VERSION 5.7 ;
  NOWIREEXTENSIONATPIN ON ;
  DIVIDERCHAR "/" ;
  BUSBITCHARS "[]" ;
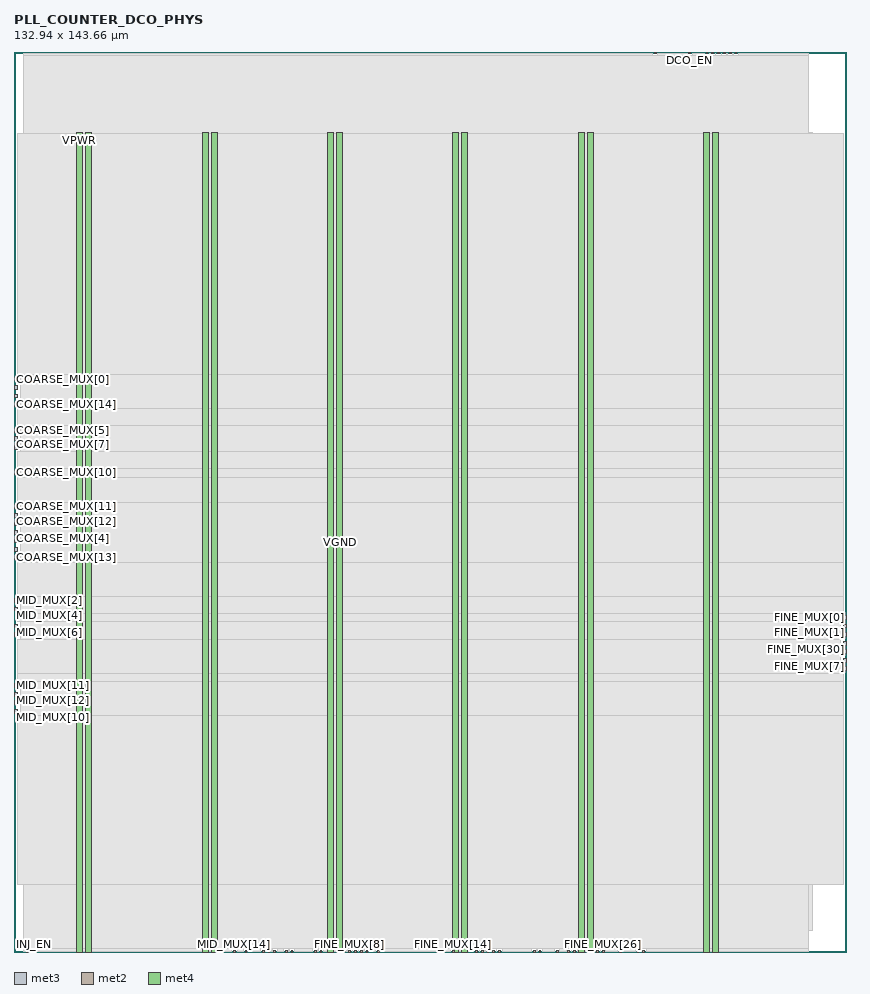
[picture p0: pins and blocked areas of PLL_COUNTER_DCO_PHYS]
MACRO PLL_COUNTER_DCO_PHYS
  CLASS BLOCK ;
  FOREIGN PLL_COUNTER_DCO_PHYS ;
  ORIGIN 0.000 0.000 ;
  SIZE 132.940 BY 143.660 ;
  PIN COARSE_MUX[0]
    DIRECTION INPUT ;
    USE SIGNAL ;
    ANTENNAGATEAREA 0.213000 ;
    PORT
      LAYER met3 ;
        RECT 0.000 91.160 0.600 91.760 ;
    END
  END COARSE_MUX[0]
  PIN COARSE_MUX[10]
    DIRECTION INPUT ;
    USE SIGNAL ;
    ANTENNAGATEAREA 0.213000 ;
    PORT
      LAYER met3 ;
        RECT 0.000 76.200 0.600 76.800 ;
    END
  END COARSE_MUX[10]
  PIN COARSE_MUX[11]
    DIRECTION INPUT ;
    USE SIGNAL ;
    ANTENNAGATEAREA 0.213000 ;
    PORT
      LAYER met3 ;
        RECT 0.000 70.760 0.600 71.360 ;
    END
  END COARSE_MUX[11]
  PIN COARSE_MUX[12]
    DIRECTION INPUT ;
    USE SIGNAL ;
    ANTENNAGATEAREA 0.213000 ;
    PORT
      LAYER met3 ;
        RECT 0.000 69.400 0.600 70.000 ;
    END
  END COARSE_MUX[12]
  PIN COARSE_MUX[13]
    DIRECTION INPUT ;
    USE SIGNAL ;
    ANTENNAGATEAREA 0.213000 ;
    PORT
      LAYER met3 ;
        RECT 0.000 62.600 0.600 63.200 ;
    END
  END COARSE_MUX[13]
  PIN COARSE_MUX[14]
    DIRECTION INPUT ;
    USE SIGNAL ;
    ANTENNAGATEAREA 0.213000 ;
    PORT
      LAYER met3 ;
        RECT 0.000 87.080 0.600 87.680 ;
    END
  END COARSE_MUX[14]
  PIN COARSE_MUX[1]
    DIRECTION INPUT ;
    USE SIGNAL ;
    ANTENNAGATEAREA 0.213000 ;
    PORT
      LAYER met3 ;
        RECT 0.000 89.800 0.600 90.400 ;
    END
  END COARSE_MUX[1]
  PIN COARSE_MUX[2]
    DIRECTION INPUT ;
    USE SIGNAL ;
    ANTENNAGATEAREA 0.213000 ;
    PORT
      LAYER met3 ;
        RECT 0.000 68.040 0.600 68.640 ;
    END
  END COARSE_MUX[2]
  PIN COARSE_MUX[3]
    DIRECTION INPUT ;
    USE SIGNAL ;
    ANTENNAGATEAREA 0.213000 ;
    PORT
      LAYER met3 ;
        RECT 0.000 88.440 0.600 89.040 ;
    END
  END COARSE_MUX[3]
  PIN COARSE_MUX[4]
    DIRECTION INPUT ;
    USE SIGNAL ;
    ANTENNAGATEAREA 0.213000 ;
    PORT
      LAYER met3 ;
        RECT 0.000 66.680 0.600 67.280 ;
    END
  END COARSE_MUX[4]
  PIN COARSE_MUX[5]
    DIRECTION INPUT ;
    USE SIGNAL ;
    ANTENNAGATEAREA 0.213000 ;
    PORT
      LAYER met3 ;
        RECT 0.000 83.000 0.600 83.600 ;
    END
  END COARSE_MUX[5]
  PIN COARSE_MUX[6]
    DIRECTION INPUT ;
    USE SIGNAL ;
    ANTENNAGATEAREA 0.213000 ;
    PORT
      LAYER met3 ;
        RECT 0.000 63.960 0.600 64.560 ;
    END
  END COARSE_MUX[6]
  PIN COARSE_MUX[7]
    DIRECTION INPUT ;
    USE SIGNAL ;
    ANTENNAGATEAREA 0.213000 ;
    PORT
      LAYER met3 ;
        RECT 0.000 81.640 0.600 82.240 ;
    END
  END COARSE_MUX[7]
  PIN COARSE_MUX[8]
    DIRECTION INPUT ;
    USE SIGNAL ;
    ANTENNAGATEAREA 0.213000 ;
    PORT
      LAYER met3 ;
        RECT 0.000 65.320 0.600 65.920 ;
    END
  END COARSE_MUX[8]
  PIN COARSE_MUX[9]
    DIRECTION INPUT ;
    USE SIGNAL ;
    ANTENNAGATEAREA 0.213000 ;
    PORT
      LAYER met3 ;
        RECT 0.000 80.280 0.600 80.880 ;
    END
  END COARSE_MUX[9]
  PIN DCO_EN
    DIRECTION INPUT ;
    USE SIGNAL ;
    ANTENNAGATEAREA 0.213000 ;
    PORT
      LAYER met2 ;
        RECT 107.730 143.380 108.010 143.660 ;
    END
  END DCO_EN
  PIN FINE_MUX[0]
    DIRECTION INPUT ;
    USE SIGNAL ;
    ANTENNAGATEAREA 0.213000 ;
    PORT
      LAYER met3 ;
        RECT 132.340 53.080 132.940 53.680 ;
    END
  END FINE_MUX[0]
  PIN FINE_MUX[10]
    DIRECTION INPUT ;
    USE SIGNAL ;
    ANTENNAGATEAREA 0.213000 ;
    PORT
      LAYER met2 ;
        RECT 58.050 0.000 58.330 0.280 ;
    END
  END FINE_MUX[10]
  PIN FINE_MUX[11]
    DIRECTION INPUT ;
    USE SIGNAL ;
    ANTENNAGATEAREA 0.213000 ;
    PORT
      LAYER met2 ;
        RECT 100.370 0.000 100.650 0.280 ;
    END
  END FINE_MUX[11]
  PIN FINE_MUX[12]
    DIRECTION INPUT ;
    USE SIGNAL ;
    ANTENNAGATEAREA 0.213000 ;
    PORT
      LAYER met2 ;
        RECT 55.290 0.000 55.570 0.280 ;
    END
  END FINE_MUX[12]
  PIN FINE_MUX[13]
    DIRECTION INPUT ;
    USE SIGNAL ;
    ANTENNAGATEAREA 0.213000 ;
    PORT
      LAYER met2 ;
        RECT 99.450 0.000 99.730 0.280 ;
    END
  END FINE_MUX[13]
  PIN FINE_MUX[14]
    DIRECTION INPUT ;
    USE SIGNAL ;
    ANTENNAGATEAREA 0.213000 ;
    PORT
      LAYER met2 ;
        RECT 70.010 0.000 70.290 0.280 ;
    END
  END FINE_MUX[14]
  PIN FINE_MUX[15]
    DIRECTION INPUT ;
    USE SIGNAL ;
    ANTENNAGATEAREA 0.213000 ;
    PORT
      LAYER met2 ;
        RECT 96.690 0.000 96.970 0.280 ;
    END
  END FINE_MUX[15]
  PIN FINE_MUX[16]
    DIRECTION INPUT ;
    USE SIGNAL ;
    ANTENNAGATEAREA 0.213000 ;
    PORT
      LAYER met2 ;
        RECT 74.610 0.000 74.890 0.280 ;
    END
  END FINE_MUX[16]
  PIN FINE_MUX[17]
    DIRECTION INPUT ;
    USE SIGNAL ;
    ANTENNAGATEAREA 0.213000 ;
    PORT
      LAYER met2 ;
        RECT 89.330 0.000 89.610 0.280 ;
    END
  END FINE_MUX[17]
  PIN FINE_MUX[18]
    DIRECTION INPUT ;
    USE SIGNAL ;
    ANTENNAGATEAREA 0.213000 ;
    PORT
      LAYER met2 ;
        RECT 73.690 0.000 73.970 0.280 ;
    END
  END FINE_MUX[18]
  PIN FINE_MUX[19]
    DIRECTION INPUT ;
    USE SIGNAL ;
    ANTENNAGATEAREA 0.213000 ;
    PORT
      LAYER met2 ;
        RECT 88.410 0.000 88.690 0.280 ;
    END
  END FINE_MUX[19]
  PIN FINE_MUX[1]
    DIRECTION INPUT ;
    USE SIGNAL ;
    ANTENNAGATEAREA 0.213000 ;
    PORT
      LAYER met3 ;
        RECT 132.340 51.720 132.940 52.320 ;
    END
  END FINE_MUX[1]
  PIN FINE_MUX[20]
    DIRECTION INPUT ;
    USE SIGNAL ;
    ANTENNAGATEAREA 0.213000 ;
    PORT
      LAYER met2 ;
        RECT 83.810 0.000 84.090 0.280 ;
    END
  END FINE_MUX[20]
  PIN FINE_MUX[21]
    DIRECTION INPUT ;
    USE SIGNAL ;
    ANTENNAGATEAREA 0.213000 ;
    PORT
      LAYER met2 ;
        RECT 86.570 0.000 86.850 0.280 ;
    END
  END FINE_MUX[21]
  PIN FINE_MUX[22]
    DIRECTION INPUT ;
    USE SIGNAL ;
    ANTENNAGATEAREA 0.213000 ;
    PORT
      LAYER met2 ;
        RECT 54.370 0.000 54.650 0.280 ;
    END
  END FINE_MUX[22]
  PIN FINE_MUX[23]
    DIRECTION INPUT ;
    USE SIGNAL ;
    ANTENNAGATEAREA 0.213000 ;
    PORT
      LAYER met2 ;
        RECT 77.370 0.000 77.650 0.280 ;
    END
  END FINE_MUX[23]
  PIN FINE_MUX[24]
    DIRECTION INPUT ;
    USE SIGNAL ;
    ANTENNAGATEAREA 0.213000 ;
    PORT
      LAYER met2 ;
        RECT 82.890 0.000 83.170 0.280 ;
    END
  END FINE_MUX[24]
  PIN FINE_MUX[25]
    DIRECTION INPUT ;
    USE SIGNAL ;
    ANTENNAGATEAREA 0.213000 ;
    PORT
      LAYER met2 ;
        RECT 76.450 0.000 76.730 0.280 ;
    END
  END FINE_MUX[25]
  PIN FINE_MUX[26]
    DIRECTION INPUT ;
    USE SIGNAL ;
    ANTENNAGATEAREA 0.213000 ;
    PORT
      LAYER met2 ;
        RECT 93.930 0.000 94.210 0.280 ;
    END
  END FINE_MUX[26]
  PIN FINE_MUX[27]
    DIRECTION INPUT ;
    USE SIGNAL ;
    ANTENNAGATEAREA 0.213000 ;
    PORT
      LAYER met2 ;
        RECT 75.530 0.000 75.810 0.280 ;
    END
  END FINE_MUX[27]
  PIN FINE_MUX[28]
    DIRECTION INPUT ;
    USE SIGNAL ;
    ANTENNAGATEAREA 0.213000 ;
    PORT
      LAYER met2 ;
        RECT 93.010 0.000 93.290 0.280 ;
    END
  END FINE_MUX[28]
  PIN FINE_MUX[29]
    DIRECTION INPUT ;
    USE SIGNAL ;
    ANTENNAGATEAREA 0.213000 ;
    PORT
      LAYER met2 ;
        RECT 56.210 0.000 56.490 0.280 ;
    END
  END FINE_MUX[29]
  PIN FINE_MUX[2]
    DIRECTION INPUT ;
    USE SIGNAL ;
    ANTENNAGATEAREA 0.213000 ;
    PORT
      LAYER met2 ;
        RECT 48.850 0.000 49.130 0.280 ;
    END
  END FINE_MUX[2]
  PIN FINE_MUX[30]
    DIRECTION INPUT ;
    USE SIGNAL ;
    ANTENNAGATEAREA 0.213000 ;
    PORT
      LAYER met3 ;
        RECT 132.340 49.000 132.940 49.600 ;
    END
  END FINE_MUX[30]
  PIN FINE_MUX[3]
    DIRECTION INPUT ;
    USE SIGNAL ;
    ANTENNAGATEAREA 0.213000 ;
    PORT
      LAYER met3 ;
        RECT 132.340 50.360 132.940 50.960 ;
    END
  END FINE_MUX[3]
  PIN FINE_MUX[4]
    DIRECTION INPUT ;
    USE SIGNAL ;
    ANTENNAGATEAREA 0.213000 ;
    PORT
      LAYER met2 ;
        RECT 47.930 0.000 48.210 0.280 ;
    END
  END FINE_MUX[4]
  PIN FINE_MUX[5]
    DIRECTION INPUT ;
    USE SIGNAL ;
    ANTENNAGATEAREA 0.213000 ;
    PORT
      LAYER met3 ;
        RECT 132.340 47.640 132.940 48.240 ;
    END
  END FINE_MUX[5]
  PIN FINE_MUX[6]
    DIRECTION INPUT ;
    USE SIGNAL ;
    ANTENNAGATEAREA 0.213000 ;
    PORT
      LAYER met2 ;
        RECT 52.530 0.000 52.810 0.280 ;
    END
  END FINE_MUX[6]
  PIN FINE_MUX[7]
    DIRECTION INPUT ;
    USE SIGNAL ;
    ANTENNAGATEAREA 0.213000 ;
    PORT
      LAYER met3 ;
        RECT 132.340 46.280 132.940 46.880 ;
    END
  END FINE_MUX[7]
  PIN FINE_MUX[8]
    DIRECTION INPUT ;
    USE SIGNAL ;
    ANTENNAGATEAREA 0.213000 ;
    PORT
      LAYER met2 ;
        RECT 53.450 0.000 53.730 0.280 ;
    END
  END FINE_MUX[8]
  PIN FINE_MUX[9]
    DIRECTION INPUT ;
    USE SIGNAL ;
    ANTENNAGATEAREA 0.213000 ;
    PORT
      LAYER met3 ;
        RECT 132.340 44.920 132.940 45.520 ;
    END
  END FINE_MUX[9]
  PIN INJ_EDGE
    DIRECTION OUTPUT ;
    USE SIGNAL ;
    ANTENNADIFFAREA 0.504100 ;
    PORT
      LAYER met2 ;
        RECT 113.250 143.380 113.530 143.660 ;
    END
  END INJ_EDGE
  PIN INJ_EN
    DIRECTION INPUT ;
    USE SIGNAL ;
    PORT
      LAYER met2 ;
        RECT 1.930 0.000 2.210 0.280 ;
    END
  END INJ_EN
  PIN MID_MUX[0]
    DIRECTION INPUT ;
    USE SIGNAL ;
    ANTENNAGATEAREA 0.213000 ;
    PORT
      LAYER met2 ;
        RECT 44.250 0.000 44.530 0.280 ;
    END
  END MID_MUX[0]
  PIN MID_MUX[10]
    DIRECTION INPUT ;
    USE SIGNAL ;
    ANTENNAGATEAREA 0.213000 ;
    PORT
      LAYER met3 ;
        RECT 0.000 38.120 0.600 38.720 ;
    END
  END MID_MUX[10]
  PIN MID_MUX[11]
    DIRECTION INPUT ;
    USE SIGNAL ;
    ANTENNAGATEAREA 0.213000 ;
    PORT
      LAYER met3 ;
        RECT 0.000 42.200 0.600 42.800 ;
    END
  END MID_MUX[11]
  PIN MID_MUX[12]
    DIRECTION INPUT ;
    USE SIGNAL ;
    ANTENNAGATEAREA 0.213000 ;
    PORT
      LAYER met3 ;
        RECT 0.000 40.840 0.600 41.440 ;
    END
  END MID_MUX[12]
  PIN MID_MUX[13]
    DIRECTION INPUT ;
    USE SIGNAL ;
    ANTENNAGATEAREA 0.213000 ;
    PORT
      LAYER met3 ;
        RECT 0.000 39.480 0.600 40.080 ;
    END
  END MID_MUX[13]
  PIN MID_MUX[14]
    DIRECTION INPUT ;
    USE SIGNAL ;
    ANTENNAGATEAREA 0.213000 ;
    PORT
      LAYER met2 ;
        RECT 35.050 0.000 35.330 0.280 ;
    END
  END MID_MUX[14]
  PIN MID_MUX[1]
    DIRECTION INPUT ;
    USE SIGNAL ;
    ANTENNAGATEAREA 0.213000 ;
    PORT
      LAYER met2 ;
        RECT 43.330 0.000 43.610 0.280 ;
    END
  END MID_MUX[1]
  PIN MID_MUX[2]
    DIRECTION INPUT ;
    USE SIGNAL ;
    ANTENNAGATEAREA 0.213000 ;
    PORT
      LAYER met3 ;
        RECT 0.000 55.800 0.600 56.400 ;
    END
  END MID_MUX[2]
  PIN MID_MUX[3]
    DIRECTION INPUT ;
    USE SIGNAL ;
    ANTENNAGATEAREA 0.213000 ;
    PORT
      LAYER met2 ;
        RECT 41.490 0.000 41.770 0.280 ;
    END
  END MID_MUX[3]
  PIN MID_MUX[4]
    DIRECTION INPUT ;
    USE SIGNAL ;
    ANTENNAGATEAREA 0.213000 ;
    PORT
      LAYER met3 ;
        RECT 0.000 54.440 0.600 55.040 ;
    END
  END MID_MUX[4]
  PIN MID_MUX[5]
    DIRECTION INPUT ;
    USE SIGNAL ;
    ANTENNAGATEAREA 0.213000 ;
    PORT
      LAYER met2 ;
        RECT 40.570 0.000 40.850 0.280 ;
    END
  END MID_MUX[5]
  PIN MID_MUX[6]
    DIRECTION INPUT ;
    USE SIGNAL ;
    ANTENNAGATEAREA 0.213000 ;
    PORT
      LAYER met3 ;
        RECT 0.000 51.720 0.600 52.320 ;
    END
  END MID_MUX[6]
  PIN MID_MUX[7]
    DIRECTION INPUT ;
    USE SIGNAL ;
    ANTENNAGATEAREA 0.213000 ;
    PORT
      LAYER met2 ;
        RECT 39.650 0.000 39.930 0.280 ;
    END
  END MID_MUX[7]
  PIN MID_MUX[8]
    DIRECTION INPUT ;
    USE SIGNAL ;
    ANTENNAGATEAREA 0.213000 ;
    PORT
      LAYER met3 ;
        RECT 0.000 50.360 0.600 50.960 ;
    END
  END MID_MUX[8]
  PIN MID_MUX[9]
    DIRECTION INPUT ;
    USE SIGNAL ;
    ANTENNAGATEAREA 0.213000 ;
    PORT
      LAYER met2 ;
        RECT 36.890 0.000 37.170 0.280 ;
    END
  END MID_MUX[9]
  PIN MID_OUT
    DIRECTION OUTPUT ;
    USE SIGNAL ;
    ANTENNADIFFAREA 0.504100 ;
    PORT
      LAYER met2 ;
        RECT 111.410 143.380 111.690 143.660 ;
    END
  END MID_OUT
  PIN OUT
    DIRECTION OUTPUT ;
    USE SIGNAL ;
    ANTENNADIFFAREA 0.504100 ;
    PORT
      LAYER met2 ;
        RECT 110.490 143.380 110.770 143.660 ;
    END
  END OUT
  PIN REF
    DIRECTION INPUT ;
    USE SIGNAL ;
    ANTENNAGATEAREA 0.654000 ;
    PORT
      LAYER met2 ;
        RECT 112.330 143.380 112.610 143.660 ;
    END
  END REF
  PIN SS_BBPD[0]
    DIRECTION OUTPUT ;
    USE SIGNAL ;
    ANTENNADIFFAREA 0.504100 ;
    PORT
      LAYER met2 ;
        RECT 115.090 143.380 115.370 143.660 ;
    END
  END SS_BBPD[0]
  PIN SS_BBPD[1]
    DIRECTION OUTPUT ;
    USE SIGNAL ;
    ANTENNADIFFAREA 0.504100 ;
    PORT
      LAYER met2 ;
        RECT 114.170 143.380 114.450 143.660 ;
    END
  END SS_BBPD[1]
  PIN TICK
    DIRECTION INPUT ;
    USE SIGNAL ;
    ANTENNAGATEAREA 2.703000 ;
    PORT
      LAYER met2 ;
        RECT 102.210 143.380 102.490 143.660 ;
    END
  END TICK
  PIN VGND
    DIRECTION INOUT ;
    USE GROUND ;
    PORT
      LAYER met4 ;
        RECT 11.480 0.000 12.440 130.800 ;
    END
    PORT
      LAYER met4 ;
        RECT 31.480 0.000 32.440 130.800 ;
    END
    PORT
      LAYER met4 ;
        RECT 51.480 0.000 52.440 130.800 ;
    END
    PORT
      LAYER met4 ;
        RECT 71.480 0.000 72.440 130.800 ;
    END
    PORT
      LAYER met4 ;
        RECT 91.480 0.000 92.440 130.800 ;
    END
    PORT
      LAYER met4 ;
        RECT 111.480 0.000 112.440 130.800 ;
    END
  END VGND
  PIN VPWR
    DIRECTION INOUT ;
    USE POWER ;
    PORT
      LAYER met4 ;
        RECT 10.040 0.000 11.000 130.800 ;
    END
    PORT
      LAYER met4 ;
        RECT 30.040 0.000 31.000 130.800 ;
    END
    PORT
      LAYER met4 ;
        RECT 50.040 0.000 51.000 130.800 ;
    END
    PORT
      LAYER met4 ;
        RECT 70.040 0.000 71.000 130.800 ;
    END
    PORT
      LAYER met4 ;
        RECT 90.040 0.000 91.000 130.800 ;
    END
    PORT
      LAYER met4 ;
        RECT 110.040 0.000 111.000 130.800 ;
    END
  END VPWR
  OBS
      LAYER nwell ;
        RECT 5.330 10.795 127.610 130.645 ;
      LAYER li1 ;
        RECT 5.520 10.795 127.420 130.645 ;
      LAYER met1 ;
        RECT 1.450 3.440 127.420 130.800 ;
      LAYER met2 ;
        RECT 1.470 143.100 101.930 143.380 ;
        RECT 102.770 143.100 107.450 143.380 ;
        RECT 108.290 143.100 110.210 143.380 ;
        RECT 111.050 143.100 111.130 143.380 ;
        RECT 111.970 143.100 112.050 143.380 ;
        RECT 112.890 143.100 112.970 143.380 ;
        RECT 113.810 143.100 113.890 143.380 ;
        RECT 114.730 143.100 114.810 143.380 ;
        RECT 115.650 143.100 126.870 143.380 ;
        RECT 1.470 0.560 126.870 143.100 ;
        RECT 1.470 0.070 1.650 0.560 ;
        RECT 2.490 0.070 34.770 0.560 ;
        RECT 35.610 0.070 36.610 0.560 ;
        RECT 37.450 0.070 39.370 0.560 ;
        RECT 40.210 0.070 40.290 0.560 ;
        RECT 41.130 0.070 41.210 0.560 ;
        RECT 42.050 0.070 43.050 0.560 ;
        RECT 43.890 0.070 43.970 0.560 ;
        RECT 44.810 0.070 47.650 0.560 ;
        RECT 48.490 0.070 48.570 0.560 ;
        RECT 49.410 0.070 52.250 0.560 ;
        RECT 53.090 0.070 53.170 0.560 ;
        RECT 54.010 0.070 54.090 0.560 ;
        RECT 54.930 0.070 55.010 0.560 ;
        RECT 55.850 0.070 55.930 0.560 ;
        RECT 56.770 0.070 57.770 0.560 ;
        RECT 58.610 0.070 69.730 0.560 ;
        RECT 70.570 0.070 73.410 0.560 ;
        RECT 74.250 0.070 74.330 0.560 ;
        RECT 75.170 0.070 75.250 0.560 ;
        RECT 76.090 0.070 76.170 0.560 ;
        RECT 77.010 0.070 77.090 0.560 ;
        RECT 77.930 0.070 82.610 0.560 ;
        RECT 83.450 0.070 83.530 0.560 ;
        RECT 84.370 0.070 86.290 0.560 ;
        RECT 87.130 0.070 88.130 0.560 ;
        RECT 88.970 0.070 89.050 0.560 ;
        RECT 89.890 0.070 92.730 0.560 ;
        RECT 93.570 0.070 93.650 0.560 ;
        RECT 94.490 0.070 96.410 0.560 ;
        RECT 97.250 0.070 99.170 0.560 ;
        RECT 100.010 0.070 100.090 0.560 ;
        RECT 100.930 0.070 126.870 0.560 ;
      LAYER met3 ;
        RECT 0.600 92.160 132.340 130.725 ;
        RECT 1.000 86.680 132.340 92.160 ;
        RECT 0.600 84.000 132.340 86.680 ;
        RECT 1.000 79.880 132.340 84.000 ;
        RECT 0.600 77.200 132.340 79.880 ;
        RECT 1.000 75.800 132.340 77.200 ;
        RECT 0.600 71.760 132.340 75.800 ;
        RECT 1.000 62.200 132.340 71.760 ;
        RECT 0.600 56.800 132.340 62.200 ;
        RECT 1.000 54.080 132.340 56.800 ;
        RECT 1.000 54.040 131.940 54.080 ;
        RECT 0.600 52.720 131.940 54.040 ;
        RECT 1.000 49.960 131.940 52.720 ;
        RECT 0.600 44.520 131.940 49.960 ;
        RECT 0.600 43.200 132.340 44.520 ;
        RECT 1.000 37.720 132.340 43.200 ;
        RECT 0.600 10.715 132.340 37.720 ;
  END
END PLL_COUNTER_DCO_PHYS
END LIBRARY

